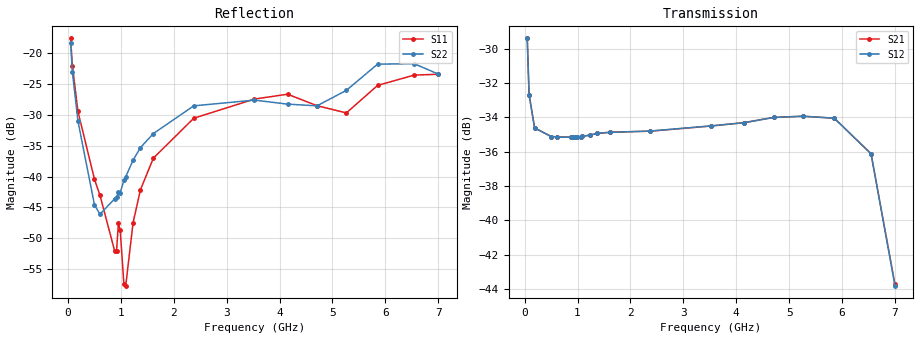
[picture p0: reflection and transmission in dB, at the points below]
! Integrated Device Technology
! Corporate Headquarters
! 6024 Silver Creek Valley Road
! San Jose, CA 95138  USA
! Phone:  1-408-284-8200
! Toll Free:  1-800-223-1366
! Webpage:  http://www.idt.com/
! Timing and RF Division
! 515 Groton Road, Suite 102
! Westford, MA 01886-6024
! Device:  F2258
! Description: Voltage Variable RF Attenuator
! Frequency:  50.0 -  6000.00 MHz
! Package:  3x3 mm Thin QFN Plastic Package: 16 pin
! Ports:  2 RF, 2 DC
!  Pin  1  = NC
!  Pin  2  = NC
!  Pin  3  = RF2  = Port 2
!  Pin  4  = GND
!  Pin  5  = Vdd
!  Pin  6  = NC
!  Pin  7  = VCTRL
!  Pin  8  = NC
!  Pin  9  = GND
!  Pin 10  = RF1  = Port 1
!  Pin 11  = NC
!  Pin 12  = NC
!  Pin 13  = NC
!  Pin 14  = NC
!  Pin 15  = NC
!  Pin 16  = NC
! Vcntrl:  2.060 Volts
! Vdd:  +3.300 Volts
! Current:  1.153 mA
! Data:  The device was measured on a the F2258 evaluation board which has
!  individual transmission lines to the RF pins.  Data was collected
!  using a calibrated network analyzer.  The evaluation board was
!  de-embedded using a TRL calibration technique.
!  The reference plane is the edge of the package pin.
! Misc:  SN 10
!  Action Tracker AT0285
! Date Measured:  2014-12-10
! Date:  2016-01-13  MJV
! Note:
!  Integrated Device Technology supplies this data as a sample of measured
!  data at the package pin for this product.  Your particular data for this
!  product may vary.
!  Data was taken at 25 degrees C.
!  Integrated Device Technology reserves the right to change this data at anytime.
!Freq_(GHz)  S11M_(dB)  S11P_(deg)  S21M_(dB)  S21P_(deg)  S12M_(dB)  S12P_(deg)  S22M_(dB)  S22P_(deg)
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# GHz S dB R 50
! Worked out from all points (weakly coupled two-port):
!   201 points, 50 MHz to 7 GHz, reference 50 ohm
!   highest |S21| = -29.41 dB at 50 MHz (marker M1); lowest = -43.7 dB at 7 GHz (marker M2)
!   lowest |S11| = -57.7 dB at 1.093 GHz (marker M3), VSWR 1.00, Z = 49.9 + j0.112 ohm
!   |S11| at or under -10 dB: start of sweep to end of sweep
!   |S22| runs from -46.1 to -18.2 dB; largest |S21 - S12| = 9.9e-05
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0.05  -17.55 -111.0  -29.41 -67.3  -29.41 -67.3  -18.25 -109.4
0.08475  -21.98 -107.4  -32.68 -47.7  -32.68 -47.7  -23.06 -102.3
0.189  -29.42 -109.4  -34.62 -24.2  -34.62 -24.2  -30.97 -94.4
0.50175  -40.44 -121.7  -35.12 -11.2  -35.12 -11.2  -44.60 -45.5
0.606  -43.06 -126.0  -35.14 -10.0  -35.15 -10.0  -46.11 -10.9
0.884  -52.11 166.4  -35.15 -8.6  -35.16 -8.5  -43.59 37.9
0.91875  -52.10 150.6  -35.15 -8.5  -35.15 -8.5  -43.34 40.4
0.9535  -47.59 -162.5  -35.15 -8.4  -35.16 -8.4  -42.58 68.1
0.98825  -48.70 -173.8  -35.14 -8.3  -35.14 -8.3  -42.61 63.8
1.05775  -57.51 154.7  -35.12 -8.2  -35.12 -8.2  -40.60 54.0
1.0925  -57.72 120.4  -35.11 -8.1  -35.11 -8.1  -40.03 52.3
1.2315  -47.47 46.1  -35.04 -8.2  -35.04 -8.2  -37.35 41.9
1.3705  -42.15 36.7  -34.94 -8.7  -34.94 -8.7  -35.29 37.9
1.61375  -37.01 32.6  -34.87 -10.0  -34.88 -10.0  -33.02 32.1
2.37825  -30.52 48.1  -34.81 -13.7  -34.80 -13.7  -28.51 30.8
3.525  -27.41 91.6  -34.51 -20.3  -34.50 -20.4  -27.58 57.8
4.1505  -26.62 105.0  -34.31 -24.8  -34.32 -24.9  -28.23 67.3
4.7065  -28.48 95.6  -34.01 -29.6  -34.01 -29.6  -28.51 49.4
5.2625  -29.66 54.3  -33.94 -35.6  -33.94 -35.7  -26.00 12.4
5.85325  -25.19 29.8  -34.06 -46.2  -34.05 -46.2  -21.73 -7.9
6.54825  -23.51 45.1  -36.12 -66.5  -36.13 -66.5  -21.68 -42.2
7  -23.38 84.5  -43.72 -62.2  -43.80 -61.8  -23.35 -128.5
